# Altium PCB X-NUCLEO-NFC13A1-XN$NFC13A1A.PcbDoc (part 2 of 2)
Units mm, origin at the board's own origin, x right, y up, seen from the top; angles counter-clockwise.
Board outline 103.96 x 54 mm, 4 copper layers (Top Layer, F2-GND, F3, Bottom Layer), stack 1.17 mm thick; 113 components, 73 nets, 268 pads, 235 vias.

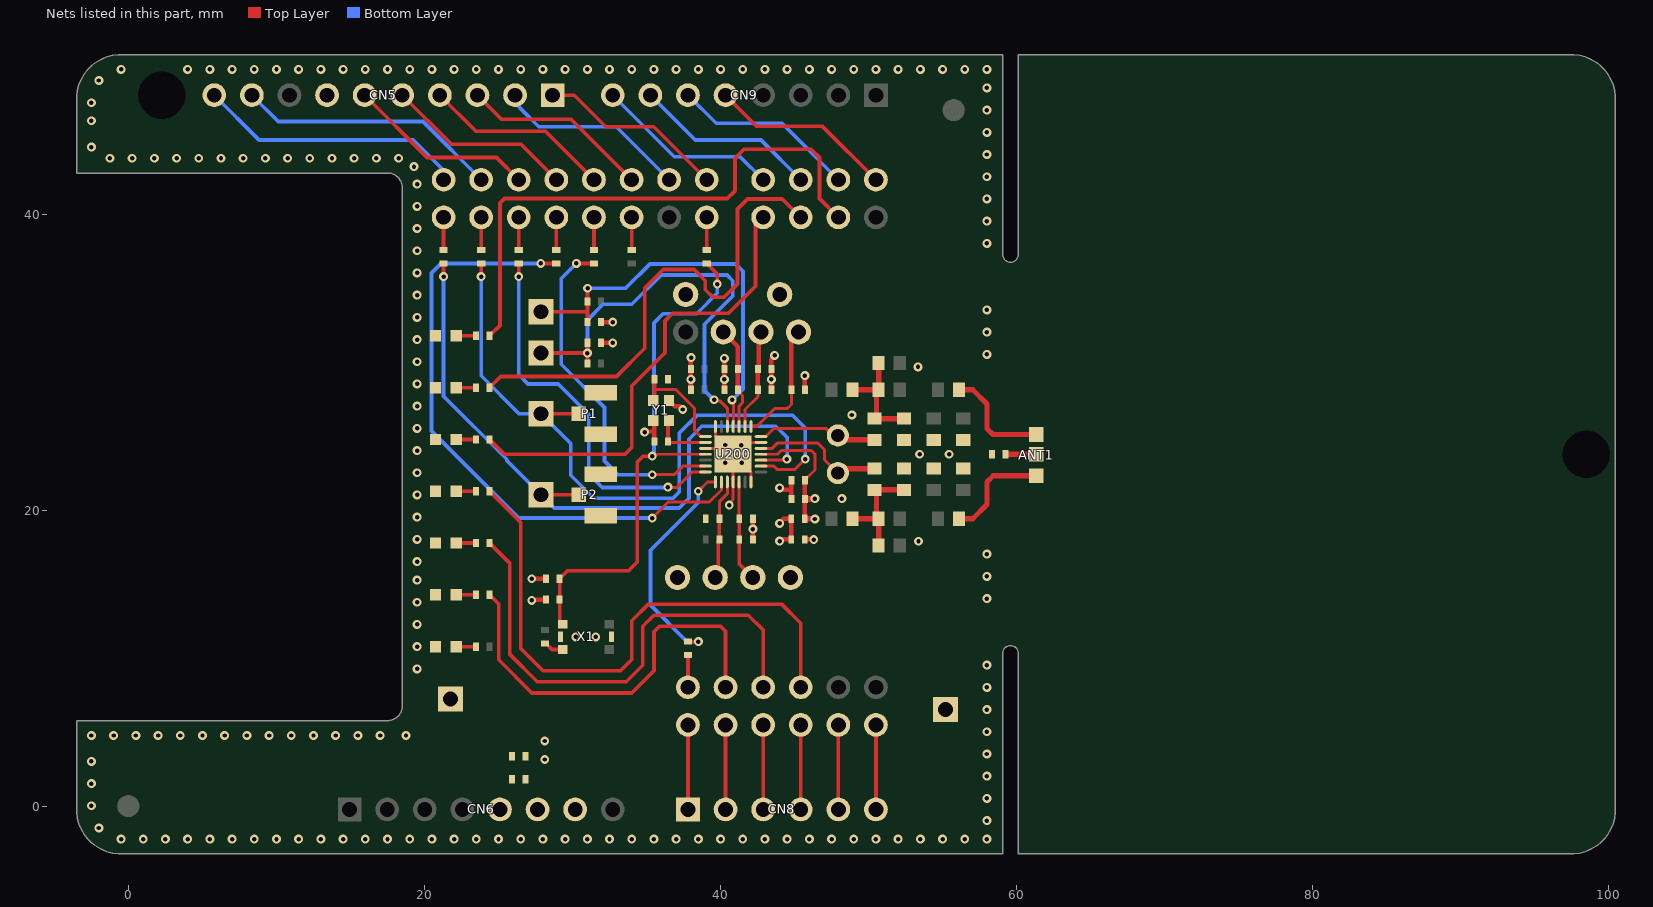
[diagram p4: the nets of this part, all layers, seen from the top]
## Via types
v1: diameter 0.6, hole 0.3, Top Layer to Bottom Layer, 225 vias
v2: diameter 1, hole 0.5, Top Layer to Bottom Layer, 10 vias

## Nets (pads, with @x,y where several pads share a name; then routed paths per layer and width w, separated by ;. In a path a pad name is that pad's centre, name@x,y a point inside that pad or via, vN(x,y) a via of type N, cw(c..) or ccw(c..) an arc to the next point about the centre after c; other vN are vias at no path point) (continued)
GND: C1.2 C2.2 C3.2 C4.2 C5.2 C6.2 C7.2 C8.2 C9.2 C10.2 C11.2 C12.2 C13.2 C14.2 C15.2 C16.2 C17.2 C22.1 C27.2 C28.2 C29.2 C30.1 C31.1 C32.1 C37.2 CN5.7 CN6.6 CN6.7 LED1.2 LED2.2 LED3.2 LED4.2 LED5.2 LED6.2 LED7.2 P1.2 P1.3 P2.2 P2.3 R17.1 R24.1 TP1.1 TP2.1 TP13.1 TP14.1 TP15.1 TP16.1 U200.4 U200.7 U200.13 U200.21 U200.24 U200.29 X1.5 X1.6 Y1.2 Y1.4 | length 28.1
  Top Layer w0.2: U200.24@38.993,24.17 40.118,24.17 U200.29@40.293,24.345 ; U200.21@39.668,25.645 39.668,24.97 40.243,24.395 v1(40.343,24.395) ; v1(40.601,20.329) 40.601,20.437 40.868,20.704 40.868,22.62 v1(41.443,23.195) 42.068,22.57 U200.7@42.068,21.895 U200.7@42.068,21.57 ; v1(41.418,24.37) 41.618,24.57 U200.13@42.743,24.57
  Top Layer w0.3: v1(27.252,13.897) 27.285,13.93 28.194,13.93 C2.2@28.227,13.963 ; v1(27.253,15.36) R17.1@28.227,15.36 ; C37.2@31.934,31.302 32.716,31.302 v1(32.73,31.288) ; C22.1@31.934,32.699 v1(32.73,32.699) ; v1(34.885,25.27) 34.922,25.307 35.542,25.307 ; Y1.4@35.474,26.053 35.542,25.985 35.542,25.307 ; C7.2@35.542,24.628 35.542,25.307 ; Y1.2@36.526,27.403 36.929,27 37.252,27 v1(37.458,26.793) ; C16.2@38.006,28.13 v1(38.006,28.828) C15.2@38.006,29.528 38.012,29.533 38.012,30.292 v1(38.018,30.297) ; C14.2@40.27,28.13 v1(40.27,28.829) C13.2@40.27,29.528 v1(40.27,30.249) ; C11.2@42.191,18.013 42.193,18.015 42.193,18.714 42.191,18.716 42.193,18.719 42.193,19.407 C12.2@42.191,19.41 ; C10.2@43.449,28.13 v1(43.449,28.829) C9.2@43.449,29.528 43.449,30.176 43.668,30.395 v1(43.668,30.45) v1@43.668,30.476 ; v1@43.992,21.381 44.798,21.381 ; C4.2@44.798,20.741 44.798,21.381 ; C5.2@44.798,22.022 44.798,21.381 ; C3.2@45.702,18.013 46.297,18.013 v1(46.31,18) ; C17.2@45.713,28.13 v1(45.713,29.079)
  other v1: -0.49,-2.23 1.01,-2.23 2.51,-2.23 4.01,-2.23 5.51,-2.23 7.01,-2.23 8.51,-2.23 10.01,-2.23 11.51,-2.23 13.01,-2.23 14.51,-2.23 16.01,-2.23 17.51,-2.23 19.01,-2.23 20.51,-2.23 22.01,-2.23 23.51,-2.23 25.01,-2.23 26.51,-2.23 28.01,-2.23 29.51,-2.23 31.01,-2.23 32.51,-2.23 34.01,-2.23 35.51,-2.23 37.01,-2.23 38.51,-2.23 40.01,-2.23 41.51,-2.23 43.01,-2.23 44.51,-2.23 46.01,-2.23 47.51,-2.23 49.01,-2.23 50.51,-2.23 52.01,-2.23 53.51,-2.23 55.01,-2.23 56.51,-2.23 58.01,-2.23 -1.99,-1.48 58.01,-0.98 -2.49,0.02 58.01,0.52 -2.49,1.52 58.01,2.02 -2.49,3.02 58.01,3.52 -2.49,4.77 -0.99,4.77 0.51,4.77 2.01,4.77 3.51,4.77 5.01,4.77 6.51,4.77 8.01,4.77 9.51,4.77 11.01,4.77 12.51,4.77 14.01,4.77 15.51,4.77 17.01,4.77 18.76,4.77 58.01,5.02 58.01,6.52 58.01,8.02 19.51,9.27 58.01,9.52 19.51,10.77 30.233,11.431 31.582,11.431 19.51,12.27 19.51,13.77 58.01,14.02 19.51,15.27 58.01,15.52 19.51,16.52 58.01,17.02 53.385,17.895 19.51,18.02 42.196,18.716 19.51,19.52 48.213,20.77 19.51,21.02 44,21.5 19.51,22.52 40.318,23.195 53.456,23.77 55.457,23.77 19.51,24.02 19.51,25.52 48.88,26.42 19.51,27.02 19.51,28.52 53.352,29.671 19.51,30.02 58.01,30.52 19.51,31.52 58.01,32.02 19.51,33.02 58.01,33.52 19.51,34.52 19.51,36.02 19.51,37.52 58.01,38.02 19.51,39.02 58.01,39.52 19.51,40.52 58.01,41.02 19.51,42.02 58.01,42.52 19.3,43.2 -1.24,43.77 0.26,43.77 1.76,43.77 3.26,43.77 4.76,43.77 6.26,43.77 7.76,43.77 9.26,43.77 10.76,43.77 12.26,43.77 13.76,43.77 15.26,43.77 16.76,43.77 18.26,43.77 58.01,44.02 -2.49,44.52 58.01,45.52 -2.49,46.3 58.01,47.02 -2.49,47.52 58.01,48.52 -1.99,49.02 -0.49,49.77 4.01,49.77 5.51,49.77 7.01,49.77 8.51,49.77 10.01,49.77 11.51,49.77 13.01,49.77 14.51,49.77 16.01,49.77 17.51,49.77 19.01,49.77 20.51,49.77 22.01,49.77 23.51,49.77 25.01,49.77 26.51,49.77 28.01,49.77 29.51,49.77 31.01,49.77 32.51,49.77 34.01,49.77 35.51,49.77 37.01,49.77 38.51,49.77 40.01,49.77 41.51,49.77 43.01,49.77 44.51,49.77 46.01,49.77 47.51,49.77 49.01,49.77 50.51,49.77 52.01,49.77 53.51,49.77 55.01,49.77 56.51,49.77 58.01,49.77
IO1: R15.2 ST1.1 | length 2.2
  Top Layer w0.25: R15.2@21.3,37.578 ST1.1@21.3,39.775
IO2: R14.2 ST2.1 | length 2.2
  Top Layer w0.25: R14.2@23.84,37.578 ST2.1@23.84,39.775
IRQ_210: R11.1 U200.1 | length 15.4
  Top Layer w0.2: v1(38.505,21.27) 39.13,21.895 U200.1@39.668,21.895
  Top Layer w0.25: R11.1@37.81,11.109 v1(38.51,11.109)
  Bottom Layer w0.25: v1(38.505,21.27) 38.505,20.508 35.276,17.278 35.276,13.585 37.751,11.109 v1(38.51,11.109)
LED1: R1.2 ST12.2 | length 28.2
  Top Layer w0.25: R1.2@24.407,14.27 25.019,13.659 25.019,9.886 27.26,7.645 34.01,7.645 35.51,9.145 35.51,11.77 35.885,12.145 40.01,12.145 40.35,11.805 ST12.2@40.35,8.025
LED2: R2.2 ST14.2 | length 33.6
  Top Layer w0.25: R2.2@24.407,17.77 25.76,16.417 25.76,10.27 27.635,8.395 33.635,8.395 34.76,9.52 34.76,12.145 35.51,12.895 41.885,12.895 42.89,11.89 ST14.2@42.89,8.025
LED3: R3.2 ST16.2 | length 39.3
  Top Layer w0.25: R3.2@24.407,21.27 26.51,19.167 26.51,10.645 28.01,9.145 33.26,9.145 34.01,9.895 34.01,12.52 35.135,13.645 44.135,13.645 45.43,12.35 ST16.2@45.43,8.025
LED4: R4.2 ST9.1 | length 31.6
  Top Layer w0.25: R4.2@24.407,24.77 25.407,23.77 33.551,23.77 34.01,24.229 34.01,28.385 36.26,30.635 36.26,32.77 36.786,33.296 40.546,33.296 42.375,35.125 42.375,39.26 ST9.1@42.89,39.775
LED5: R5.2 ST11.1 | length 34.1
  Top Layer w0.25: R5.2@24.407,28.27 25.157,29.02 32.978,29.02 34.885,30.926 34.885,34.999 36.136,36.25 38.227,36.25 38.985,35.492 38.985,34.89 39.5,34.375 40.25,34.375 41.15,35.275 41.15,40.341 41.829,41.02 44.185,41.02 ST11.1@45.43,39.775
LED6: R6.2 ST13.1 | length 38.4
  Top Layer w0.25: R6.2@24.407,31.77 25.11,32.473 25.11,40.745 25.41,41.045 40.467,41.045 40.985,41.563 40.985,43.762 41.598,44.375 46.143,44.375 46.7,43.818 46.7,41.045 ST13.1@47.97,39.775
MISO_210: R12.1 U200.2 | length 42.7
  Top Layer w0.2: v1(35.4,19.461) 36.469,20.53 39.236,20.53 40.068,21.362 U200.2@40.068,21.895
  Top Layer w0.25: v1(27.866,36.663) R12.1@28.92,36.663
  Bottom Layer w0.25: v1(27.866,36.663) 21.134,36.663 20.48,36.01 20.48,25.335 26.355,19.461 v1@35.368,19.461
MOSI_210: R9.1 U200.27 | length 23.6
  Top Layer w0.2: v1@35.51,22.386 36.89,22.386 37.47,22.966 U200.27@38.993,22.966
  Top Layer w0.25: v1(30.267,36.663) R9.1@31.46,36.663
  Bottom Layer w0.25: v1(30.267,36.663) 29.25,35.647 29.25,29.845 32.164,26.931 32.164,23.309 33.087,22.386 v1(35.4,22.386) v1@35.51,22.386
NetANT1_1: ANT1.1 R20.1 | length 7.5
  Top Layer w0.35: R20.1@56.118,28.13 57.05,28.13 58.01,27.169 58.01,25.494 58.409,25.095 ANT1.1@61.335,25.095
NetANT1_2: ANT1.2 R19.1 | length 7.3
  Top Layer w0.35: R19.1@56.118,19.41 57.05,19.41 58.01,20.37 58.01,21.895 58.435,22.32 ANT1.2@61.335,22.32
NetANT1_3: ANT1.3 R24.2 | length 2.1
  Top Layer w0.35: R24.2@59.257,23.77 ANT1.3@61.335,23.77
NetC23_1: C23.1 C25.2 C26.1 C27.1 L2.1 | length 7.7
  Top Layer w0.35: C25.2@48.929,19.41 C26.1@50.696,19.41 ; L2.1@50.406,21.37 L2.1@50.696,21.37 ; C23.1@50.696,17.59 C26.1@50.696,19.41 ; C27.1@52.407,21.37 L2.1@50.696,21.37 ; C26.1@50.696,19.41 50.551,19.554 50.551,21.225 L2.1@50.696,21.37
NetC30_2: C30.2 C33.1 C34.1 C35.1 L3.1 | length 7.4
  Top Layer w0.35: C34.1@48.929,28.13 C33.1@50.696,28.13 ; C35.1@50.696,29.93 C33.1@50.696,28.13 ; C30.2@52.407,26.17 50.696,26.17 50.551,26.314 50.551,27.985 C33.1@50.696,28.13
NetCN5_1: CN5.1 ST8.2 | length 12.8
  Top Layer w0.25: CN5.1@28.666,48.03 30.125,48.03 32.26,45.895 35.5,45.895 ST8.2@39.08,42.315
NetCN5_2: CN5.2 ST7.2 | length 13
  Bottom Layer w0.25: CN5.2@26.126,48.03 ccw(c27.408,48.03) 26.501,47.124 27.73,45.895 32.96,45.895 36.335,42.52 ST7.2@36.635,42.52
NetCN5_3: CN5.3 ST6.2 | length 12.8
  Top Layer w0.25: CN5.3@23.586,48.03 25.217,46.399 29.916,46.399 ST6.2@34,42.315
NetCN5_4: CN5.4 ST5.2 | length 12.8
  Top Layer w0.25: CN5.4@21.046,48.03 23.487,45.589 28.186,45.589 ST5.2@31.46,42.315
NetCN5_5: CN5.5 ST4.2 | length 12.8
  Top Layer w0.25: CN5.5@18.506,48.03 21.83,44.706 26.529,44.706 ST4.2@28.92,42.315
NetCN5_6: CN5.6 ST3.2 | length 12.8
  Top Layer w0.25: CN5.6@15.966,48.03 20.178,43.818 24.877,43.818 ST3.2@26.38,42.315
NetCN5_9: CN5.9 ST2.2 | length 17.9
  Bottom Layer w0.25: CN5.9@8.346,48.03 10.126,46.25 19.905,46.25 ST2.2@23.84,42.315
NetCN5_10: CN5.10 ST1.2 | length 18.2
  Bottom Layer w0.25: CN5.10@5.806,48.03 8.836,45 19.25,45 21.3,42.95 ST1.2@21.3,42.315
NetCN8_1: CN8.1 ST10.1 | length 5.7
  Top Layer w0.25: CN8.1@37.81,-0.23 ST10.1@37.81,5.485
NetCN8_2: CN8.2 ST12.1 | length 5.7
  Top Layer w0.25: CN8.2@40.35,-0.23 ST12.1@40.35,5.485
NetCN8_3: CN8.3 ST14.1 | length 5.7
  Top Layer w0.25: CN8.3@42.89,-0.23 ST14.1@42.89,5.485
NetCN8_4: CN8.4 ST16.1 | length 5.7
  Top Layer w0.25: CN8.4@45.43,-0.23 ST16.1@45.43,5.485
NetCN8_5: CN8.5 ST18.1 | length 5.7
  Top Layer w0.25: CN8.5@47.97,-0.23 ST18.1@47.97,5.485
NetCN8_6: CN8.6 ST20.1 | length 5.7
  Top Layer w0.25: CN8.6@50.51,-0.23 ST20.1@50.51,5.485
NetCN9_5: CN9.5 ST15.2 | length 12.5
  Top Layer w0.25: CN9.5@40.35,48.03 42.46,45.92 46.905,45.92 ST15.2@50.51,42.315
NetCN9_6: CN9.6 ST13.2 | length 12.8
  Top Layer w0.25: ST13.2@47.939,42.579 47.939,42.346 ST13.2@47.97,42.315
  Bottom Layer w0.25: CN9.6@37.81,48.03 39.715,46.125 44.16,46.125 ST13.2@47.97,42.315
NetCN9_7: CN9.7 ST11.2 | length 12.5
  Bottom Layer w0.25: CN9.7@35.27,48.03 38.3,45 42.745,45 ST11.2@45.43,42.315
NetCN9_8: CN9.8 ST9.2 | length 12.5
  Bottom Layer w0.25: CN9.8@32.73,48.03 36.885,43.875 41.33,43.875 ST9.2@42.89,42.315
NetLED1_1: LED1.1 R1.1 | length 1.3
  Top Layer w0.25: LED1.1@22.149,14.27 R1.1@23.493,14.27
NetLED2_1: LED2.1 R2.1 | length 1.3
  Top Layer w0.25: LED2.1@22.149,17.77 R2.1@23.493,17.77
NetLED3_1: LED3.1 R3.1 | length 1.3
  Top Layer w0.25: LED3.1@22.149,21.27 R3.1@23.493,21.27
NetLED4_1: LED4.1 R4.1 | length 1.3
  Top Layer w0.25: LED4.1@22.149,24.77 R4.1@23.493,24.77
NetLED5_1: LED5.1 R5.1 | length 1.3
  Top Layer w0.25: LED5.1@22.149,28.27 R5.1@23.493,28.27
NetLED6_1: LED6.1 R6.1 | length 1.3
  Top Layer w0.25: LED6.1@22.149,31.77 R6.1@23.493,31.77
NetLED7_1: LED7.1 R7.1 | length 1.3
  Top Layer w0.25: LED7.1@22.149,10.77 R7.1@23.493,10.77
NetR16_1: R16.1 X1.2 | length 1.4
  Top Layer w0.25: R16.1@28.149,10.974 28.228,10.974 28.621,10.581 X1.2@29.349,10.581
RESET: R13.2 ST8.1 | length 2.2
  Top Layer w0.25: R13.2@39.08,37.578 ST8.1@39.08,39.775
RESET_210: C2.1 R13.1 R17.2 U200.25 X1.4 | length 36.9
  Top Layer w0.2: v1(35.4,23.645) 35.477,23.721 35.668,23.721 35.717,23.77 U200.25@38.993,23.77
  Top Layer w0.25: X1.4@29.349,12.281 29.142,12.489 C2.1@29.142,13.963 R17.2@29.142,15.36 29.677,15.895 33.798,15.895 34.385,16.482 34.385,23.24 34.79,23.645 v1(35.4,23.645) ; R13.1@39.08,36.663 39.788,35.956 v1(39.788,35.264)
  Bottom Layer w0.25: v1@35.51,23.645 35.51,32.645 36.13,33.265 38.396,33.265 39.788,34.658 v1(39.788,35.264)
RFI1: C22.2 C24.1 TP4.1 U200.18 | length 27.6
  Top Layer w0.2: U200.18@40.872,25.645 40.872,27.123 40.867,27.128 40.867,27.495 v1@40.872,27.5
  Top Layer w0.25: TP4.1@27.883,33.397 27.885,33.398 31.02,33.398 ; C22.2@31.02,32.699 31.02,33.398 ; v1(31.029,34.982) 31.02,34.972 C24.1@31.02,34.096 31.02,33.398
  Bottom Layer w0.25: v1(31.029,34.982) 33.597,34.982 35.24,36.625 41.03,36.625 41.53,36.125 41.53,28.155 v1@40.875,27.5
  other v1: 40.79,27.44
RFI2: C36.2 C37.1 TP5.1 U200.19 | length 29.4
  Top Layer w0.2: v1(39.58,27.45) 39.648,27.382 39.96,27.382 40.468,26.874 U200.19@40.468,25.645
  Top Layer w0.25: TP5.1@27.884,30.604 v1(31.02,30.604) ; C36.2@31.02,29.905 v1(31.02,30.604) ; C37.1@31.02,31.302 v1(31.02,30.604)
  Bottom Layer w0.25: v1(31.02,30.604) 31.02,32.846 32.077,33.903 34.018,33.903 35.99,35.875 40.444,35.875 40.831,35.488 40.831,34.456 38.925,32.55 38.925,28.075 v1@39.5,27.5
RFO1: J1.1 L2.2 U200.12 | length 9.2
  Top Layer w0.2: U200.12@42.743,24.17 43.497,24.17 43.847,24.52 46.588,24.52 47.038,24.07 47.038,23.401 47.514,22.925 47.897,22.925 J1.1@47.939,22.966
  Top Layer w0.25: J1.1@47.939,22.5 J1.1@47.939,22.966
  Top Layer w0.35: J1.1@48.172,22.5 48.464,22.793 L2.2@50.406,22.793
RFO2: J1.2 L3.2 U200.14 | length 8.2
  Top Layer w0.2: U200.14@42.743,24.97 43.068,24.97 43.618,25.52 47.121,25.52 J1.2@47.601,25.04
  Top Layer w0.25: J1.2@47.601,25.04 J1.2@47.647,25.04
  Top Layer w0.35: J1.2@47.647,25.04 J1.2@47.939,25.04 48.232,24.747 L3.2@50.406,24.747
SCLK_210: R10.1 U200.28 | length 26.1
  Top Layer w0.2: v1@36.486,21.52 37.051,21.52 38.101,22.57 U200.28@38.993,22.57
  Top Layer w0.25: v1(26.38,35.77) R10.1@26.38,36.663 ; v1(36.457,21.549) v1@36.486,21.52
  Bottom Layer w0.25: v1(26.38,35.77) 26.38,29.14 27,28.52 29.04,28.52 31.116,26.445 31.116,22.421 32.017,21.52 36.427,21.52 v1(36.457,21.549)
SPI_BSS: R8.2 ST6.1 | length 2.2
  Top Layer w0.25: R8.2@34.011,37.578 ST6.1@34.011,39.775
SPI_IRQ: R11.2 ST10.2 | length 2.2
  Top Layer w0.25: ST10.2@37.81,8.025 R11.2@37.81,10.195
SPI_MISO: R12.2 ST4.1 | length 2.2
  Top Layer w0.25: R12.2@28.92,37.578 ST4.1@28.92,39.775
SPI_MOSI: R9.2 ST5.1 | length 2.2
  Top Layer w0.25: R9.2@31.46,37.578 ST5.1@31.46,39.775
SPI_SCLK: R10.2 ST3.1 | length 2.2
  Top Layer w0.25: R10.2@26.38,37.578 ST3.1@26.38,39.775
TAD1_210: P1.1 R14.1 TP3.1 U200.9 | length 47.2
  Top Layer w0.2: U200.9@42.743,22.97 43.601,22.97 43.821,22.75 45.04,22.75 v1(45.735,23.445)
  Top Layer w0.25: v1(23.84,35.77) R14.1@23.84,36.663 ; TP3.1@27.883,26.51 P1.1@30.427,26.51
  Bottom Layer w0.25: v1(23.84,35.77) 23.84,29.066 26.396,26.51 TP3.1@27.883,26.51 29.894,24.499 29.894,22.358 31.451,20.801 36.797,20.801 37.221,21.225 37.221,25.201 38.415,26.395 44.885,26.395 45.735,25.545 v1(45.735,23.445)
TAD2_210: P2.1 R15.1 TP6.1 U200.10 | length 46.3
  Top Layer w0.2: U200.10@42.743,23.37 44.42,23.37 v1(44.495,23.445)
  Top Layer w0.25: v1(21.3,35.77) R15.1@21.3,36.663 ; TP6.1@27.883,21.03 P2.1@30.427,21.03 ; v1@44.4,23.445 v1(44.495,23.445)
  Bottom Layer w0.25: v1(21.3,35.77) 21.3,27.686 25.56,23.425 25.56,23.353 TP6.1@27.883,21.03 28.773,20.141 37.221,20.141 37.875,20.795 37.875,24.787 38.747,25.66 43.745,25.66 44.51,24.895 44.51,23.46 v1(44.495,23.445) v1@44.42,23.52
V_RF: C3.1 L1.2 R23.1 | length 3
  Top Layer w0.3: v1@44,19.15 44.26,19.41 L1.2@44.788,19.41 C3.1@44.788,18.013 v1@44.08,18.013
  other v1: 28.135,3.145 28.135,4.395 44,17.9 44,19.1
VBUS: C1.1 CN6.5 R23.2
VDD: C4.1 C5.1 C9.1 C10.1 L1.1 TP12.1 U200.11 U200.16 | length 16.3
  Top Layer w0.2: U200.16@41.668,25.645 41.668,26.793 42.535,27.66 C10.1@42.535,28.13 ; U200.11@42.743,23.77 43.865,23.77 44.114,24.02 46.135,24.02 46.385,23.77 46.385,22.714 C5.1@45.847,22.176
  Top Layer w0.3: C10.1@42.535,28.13 C9.1@42.535,29.528 42.585,29.578 42.585,31.877 TP12.1@42.535,31.927 ; L1.1@45.702,19.41 L1.1@45.713,19.41 ; L1.1@45.707,19.415 45.707,20.735 C4.1@45.713,20.741 C5.1@45.713,22.022
  Top Layer w0.4: L1.1@45.713,19.41 46.37,19.41 v1(46.385,19.395) ; C4.1@45.713,20.741 46.356,20.741 v1(46.385,20.77)
VDD_A: C13.1 C14.1 TP11.1 U200.17 | length 6.8
  Top Layer w0.2: C14.1@41.185,28.051 41.5,27.736 41.5,27.25 41.268,27.018 U200.17@41.268,25.645
  Top Layer w0.25: C14.1@41.185,28.051 C14.1@41.185,28.13
  Top Layer w0.3: TP11.1@40.446,31.927 40.446,31.777 41.185,31.038 C13.1@41.185,29.528 C14.1@41.185,28.13
VDD_D: C11.1 C12.1 TP10.1 U200.5 | length 6.8
  Top Layer w0.2: C12.1@41.268,19.418 U200.5@41.268,21.895
  Top Layer w0.25: C12.1@41.276,19.41 C11.1@41.276,18.013 41.276,16.361 TP10.1@42.189,15.448
VDD_DR: C17.1 TP8.1 U200.15 | length 8
  Top Layer w0.2: U200.15@42.068,25.645 42.464,25.645 43.674,26.855 44.516,26.855 44.798,27.137 C17.1@44.798,28.13
  Top Layer w0.3: C17.1@44.798,28.13 TP8.1@44.798,31.752
VDD_IO: C8.1 R18.1 TP7.1 U200.3 | length 6.1
  Top Layer w0.2: C8.1@39.927,19.41 39.927,20.555 40.468,21.096 U200.3@40.468,21.895
  Top Layer w0.25: TP7.1@39.927,16.104 39.852,16.179 39.852,17.938 R18.1@39.927,18.013 C8.1@39.927,19.41
XTI: C6.1 U200.22 Y1.3 | length 7
  Top Layer w0.2: 35.542,28.153 36.972,28.153 38.25,26.875 38.25,25.388 38.668,24.97 U200.22@38.993,24.97
  Top Layer w0.25: Y1.3@35.542,27.471 35.542,28.153 C6.1@35.542,28.829
XTO: C7.1 U200.23 Y1.1 | length 4
  Top Layer w0.2: C7.1@36.457,24.628 36.515,24.57 U200.23@38.993,24.57
  Top Layer w0.25: C7.1@36.457,24.628 Y1.1@36.457,25.983 ; Y1.1@36.657,25.983 Y1.1@36.726,26.053
pads on no net: CN5.8 CN6.1 CN6.2 CN6.3 CN6.8 CN9.1 CN9.2 CN9.3 CN9.4 MIR1.1 MIR2.1 ST7.1 ST15.1 ST18.2 ST20.2 X1.1 X1.3
copper on no net: | length 40
  Top Layer w0.2: 1.76,2.47 1.76,3.72 ; 1.76,2.47 0.51,2.47 0.51,3.72 1.76,3.72 ; 1.76,2.47 1.76,3.72 ; 1.76,2.47 3.01,2.47 ; 1.76,3.72 3.01,3.72 ; 3.01,2.47 3.01,3.72 ; 3.01,2.47 3.01,3.72 ; 3.01,2.47 4.26,2.47 ; 3.01,3.72 4.26,3.72 ; 4.26,2.47 4.26,3.72 ; 4.26,2.47 4.26,3.72 ; 4.26,2.47 5.51,2.47 5.51,3.72 4.26,3.72
  Bottom Layer w0.2: 1.76,2.47 3.01,2.47 ; 1.76,2.47 1.76,3.72 ; 1.76,2.47 0.51,2.47 0.51,3.72 1.76,3.72 ; 1.76,2.47 1.76,3.72 ; 1.76,3.72 3.01,3.72 ; 3.01,2.47 4.26,2.47 ; 3.01,2.47 3.01,3.72 ; 3.01,2.47 3.01,3.72 ; 3.01,3.72 4.26,3.72 ; 4.26,2.47 5.51,2.47 5.51,3.72 4.26,3.72 ; 4.26,2.47 4.26,3.72 ; 4.26,2.47 4.26,3.72
  other v2: 63.226,22.32 65.714,22.324 92.473,22.325 94.994,22.329 63.235,23.77 66.976,23.77 63.226,25.095 64.473,25.215 93.714,25.215 96.235,25.22

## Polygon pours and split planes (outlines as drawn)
GND on Top Layer "NONET_L03_P-001" (solid, remove dead copper, pour order 471): -3.49,50.77 58.5,50.77 58.5,-3.23 -3.49,-3.23
V_RF on Top Layer "NONET_L03_P-001" (solid, remove dead copper, pour order 468): 26.625,2.75 26.625,4.77 28.5,4.77 28.5,2.75
VBUS on Top Layer "NONET_L03_P-001" (solid, pour order 470): 26.115,-1.5 26.115,4.75 24.125,4.75 24.125,-1.5
no net on Top Solder "NONET_L03_P-001" (solid, pour order 474): 0.26,3.895 5.76,3.895 5.76,2.27 0.26,2.27
no net on Bottom Solder "NONET_L03_P-001" (solid, pour order 475): 0.26,3.895 5.76,3.895 5.76,2.27 0.26,2.27
VDD on F3 "NONET_L03_P-001" (solid, pour order 479): 48,12 36.125,12 36.125,2.25 24.375,2.25 24.375,-3.25 58.5,-3.25 58.5,50.875 -3.5,50.875 -3.5,20 45.5,20 45.5,18 48,18
3V3 on F3 "NONET_L03_P-001" (solid, pour order 477): -4.625,-3.23 23.875,-3.23 23.875,9.375 28.75,9.375 28.75,17.5 38.75,17.5 38.75,19.5 -4.625,19.5
V_RF on F3 "NONET_L03_P-001" (solid, pour order 478): 47.5,12.5 35.625,12.5 35.625,2.75 24.375,2.75 24.375,8.875 29.25,8.875 29.25,17 39.25,17 39.25,19.5 45,19.5 45,17.5 47.5,17.5
GND on F2-GND "NONET_L03_P-001" (solid, pour order 472): -3.49,50.77 58.5,50.77 58.5,-3.23 -3.49,-3.23
GND on Bottom Layer "BTM_GND" (solid, remove dead copper, pour order 473): 58.5,58.731 58.5,-11.272 -4.44,-11.272 -4.44,58.731

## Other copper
Top Layer:
  pour cut-out: 42.494,20.568 42.994,20.568 42.994,22.212 42.494,22.212
  pour cut-out: 48.113,28.188 48.822,28.188 48.822,29.807 48.113,29.807
  pour cut-out: 44.598,25.75 45.098,25.75 45.098,27 44.598,27
  pour cut-out: 42.793,26.544 43.293,26.544 43.293,27.794 42.793,27.794
  pour cut-out: 37.234,24.891 37.734,24.891 37.734,26.141 37.234,26.141
  pour cut-out: 49.724,25 53.875,25 53.875,26.375 49.724,26.375
  pour cut-out: 48.072,18.842 48.572,18.842 48.572,20.092 48.072,20.092
  pour cut-out: 48.113,27.755 48.113,27.448 48.322,27.448 48.322,27.83 48.188,27.83
  pour cut-out: 33.375,30.063 34.125,30.063 34.125,31.437 33.375,31.438
  pour cut-out: 35.954,29.062 36.25,29.062 36.25,30.218 35.954,30.218
  pour cut-out: 40.75,32.375 42,32.375 42,34.5 40.75,34.5
  pour cut-out: 54.875,25 55.875,25 55.875,26.375 54.875,26.375
  pour cut-out: 55.102,25.154 58.75,25.154 58.75,28.812 55.102,28.812
  pour cut-out: 55.102,18.75 58.5,18.75 58.5,22.386 55.102,22.386
  pour cut-out: 49.724,21 57,21 57,22.625 49.724,22.625
  pour cut-out: 50.5,23.125 51.089,23.125 51.089,24.375 50.5,24.375
  pour cut-out: 45,18.375 45.5,18.375 45.5,19.625 45,19.625
  pour cut-out: 46.375,19.375 46.875,19.375 46.875,21.5 46.375,21.5
  pour cut-out: 45.938,21.5 47.562,21.5 47.562,22.75 45.938,22.75
  pour cut-out: 37.125,43.375 41.75,43.375 41.75,44.625 37.125,44.625
  pour cut-out: 15.75,47.75 29.375,47.75 29.375,49 15.75,49
  pour cut-out: 22.875,35.25 25.125,35.25 25.125,42.315 22.875,42.315
  pour cut-out: 20.3,42.315 25.75,42.315 25.75,43.512 20.3,43.512
  pour cut-out: 31.25,29.875 31.75,29.875 31.75,31.125 31.25,31.125
  pour cut-out: 31.25,32.625 31.75,32.625 31.75,33.875 31.25,33.875
  pour cut-out: 31.875,37 33.625,37 33.625,38.25 31.875,38.25
  pour cut-out: 26.875,36.125 30.25,36.125 30.25,37.625 26.875,37.625
  pour cut-out: 31.375,34.25 31.875,34.25 31.875,35.5 31.375,35.5
  pour cut-out: 25.375,35.25 26.375,35.25 26.375,36.5 25.375,36.5
  pour cut-out: 43.25,38.75 48,38.75 48,43.25 43.25,43.25
  pour cut-out: 38.25,28.125 38.75,28.125 38.75,29.375 38.25,29.375
  pour cut-out: 36.375,30.625 40.875,30.625 40.875,31.875 36.375,31.875
  pour cut-out: 40.5,28.25 41,28.25 41,29.5 40.5,29.5
  pour cut-out: 34.375,26.25 34.875,26.25 34.875,27.75 34.375,27.75
  pour cut-out: 35.75,24.375 36.25,24.375 36.25,25.625 35.75,25.625
  pour cut-out: 39.25,18.25 39.75,18.25 39.75,20.25 39.25,20.25
  pour cut-out: 28.375,12.25 28.875,12.25 28.875,13.5 28.375,13.5
  pour cut-out: 28.125,9.5 29.875,9.5 29.875,11 28.125,11
  pour cut-out: 21,11.25 26.25,11.25 26.25,18.661 24.161,20.75 21,20.75
  pour cut-out: 34,7.375 34.375,7 46.375,7 46.375,11.75 44.25,13.875 35,13.875 34,12.875 34,8.625
  pour cut-out: 28.382,15.176 29.017,15.176 29.017,14.16 28.382,14.16
  text "- TOP LAYER -" at 34.629,56 h1.5
  text "1" at 1.01,2.72 h0.75
F2-GND:
  pour cut-out: 0.26,3.895 5.76,3.895 5.76,2.27 0.26,2.27
  text "- INT1 -" at 40,56 h1.5
  text "2" at 2.135,2.72 h0.75
F3:
  pour cut-out: 39.919,24.678 41.842,24.678 41.842,22.937 41.867,22.912 39.894,22.912
  pour cut-out: 0.26,3.895 5.76,3.895 5.76,2.27 0.26,2.27
  text "- INT2 -" at 40,56 h1.5
  text "3" at 3.385,2.72 h0.75
Bottom Layer:
  pour cut-out: 44.353,22.87 44.875,22.87 44.875,17.625 44.412,17.625
  pour cut-out: 48.369,29.909 49.114,29.909 49.114,28.375 48.386,28.375
  pour cut-out: 44.847,26.673 46.644,26.673 46.644,25.875 44.856,25.875
  pour cut-out: 40.629,37.125 41.882,37.125 41.882,36.327 40.638,36.327
  pour cut-out: 35.747,33.048 41.53,33.048 41.53,30.875 35.771,30.875
  pour cut-out: 34.122,24.798 37.125,24.798 37.125,24 34.131,24
  pour cut-out: 31.362,30.625 33.75,30.625 33.75,29.25 31.378,29.25
  pour cut-out: 27.866,37.173 31.5,37.173 31.5,36.375 27.875,36.375
  text "- BOT LAYER -" at 58.6,56.2 h1.5
  text "4" at 5.21,2.72 h0.75

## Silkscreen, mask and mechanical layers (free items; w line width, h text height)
Top Overlay:
  drawing of 444 lines, arcs and shapes, not listed
  text "- TOP OVERLAY -" at 36.375,56 h1.5
  text "GND" at 38.005,35.926 h0.7 r90
  text "GND" at 44.355,35.93 h0.7 r90
  text "VDD_A" at 40.599,33.162 h0.7 r90
  text "VDD" at 42.335,33.162 h0.7 r90
  text "VDD_DR" at 45.913,33.162 h0.7 r90
  text "RFI1" at 23.617,32.915 h0.7
  text "LED6" at 20.227,32.75 h0.7
  text "AGD" at 36.42,32.332 h0.7 r90
  text "RFI2" at 23.617,30.254 h0.7
  text "LED5" at 20.227,29.25 h0.7
  text "TAD2" at 23.617,26.17 h0.7
  text "LED4" at 20.227,25.75 h0.7
  text "RFO2" at 44.86,23.487 h0.7 r90
  text "RFO1" at 46.085,22.832 h0.7 r90
  text "LED3" at 20.227,22.25 h0.7
  text "ST25" at 81.602,22.213 h1.56 r90
  text "TAD1" at 23.617,19.446 h0.7
  text "LED2" at 20.227,18.75 h0.7
  text "LED1" at 20.344,15.25 h0.7
  text "GND" at 37.458,12.203 h0.7 r90
  text "GND" at 44.005,12.203 h0.7 r90
  text "PWR OK" at 20.017,11.82 h0.7
  text "VDD_D" at 42.481,10.804 h0.7 r90
  text "VDD_IO" at 39.998,10.221 h0.7 r90
  text "www.st.com/nucleo-nfc" at 70,8.72 h3.4 r90
  text "RESET" at 29.874,8.595 h0.7
  text "GND" at 20.128,6.292 h0.7 r90
  text "X-NUCLEO-NFC13A1" at 90.02,6.25 h4 r90
  text "GND" at 53.48,5.587 h0.7 r90
  text "V_RF" at 26.312,5.442 h0.7
  text "XN$NFC13A1A" at 9.693,2.925 h1.4
  text "Nucleo" at 10.85,-1.732 h0.7 r90
Bottom Overlay:
  drawing of 245 lines, arcs and shapes, not listed
  text "- BOTTOM OVERLAY -" at 9.625,55.25 h1.5
  text "FCCID:YCPNFC13A1" at 85.476,41.455 h5 r89.84
  text "IC:8976A-NFC13A1" at 89.55,39.76 h5 r89.95
  text "X-NUCLEO-NFC13A1" at 80.028,38.795 h4.15 r90.06
Top Paste:
  lines w0.2: 59.6,35.484 59.499,35.484 59.312,35.407 59.169,35.264 59.092,35.077 59.092,34.976 59.092,26.562 59.169,26.375 59.312,26.232 59.499,26.155 59.701,26.155 59.888,26.232 60.031,26.375 60.108,26.562 60.108,35.077 60.031,35.264 59.888,35.407 59.701,35.484 59.6,35.484 ; 59.6,35.484 59.6,35.484 ; 60.108,37.254 60.108,37.153 60.031,36.966 59.888,36.823 59.701,36.746 59.6,36.746 59.499,36.746 59.312,36.823 59.169,36.966 59.092,37.153 59.092,37.254 59.092,50.77 -0.687,50.77 -1.077,50.719 -1.458,50.617 -1.821,50.466 -2.162,50.269 -2.475,50.029 -2.753,49.751 -2.993,49.439 -3.19,49.098 -3.341,48.734 -3.443,48.353 -3.494,47.963 -3.494,47.766 -3.49,42.77 17.51,42.77 cw(c17.51,41.77) 18.51,41.77 18.51,6.77 cw(c17.51,6.77) 17.51,5.77 -3.49,5.77 -3.49,-0.427 -3.439,-0.817 -3.337,-1.196 -3.186,-1.56 -2.99,-1.9 -2.75,-2.212 -2.472,-2.49 -2.16,-2.73 -1.82,-2.926 -1.456,-3.077 -1.077,-3.179 -0.687,-3.23 59.092,-3.23 59.092,10.439 59.169,10.626 59.312,10.769 59.499,10.846 59.701,10.846 59.888,10.769 60.031,10.626 60.108,10.439 60.108,-3.23 97.664,-3.23 98.054,-3.179 98.434,-3.077 98.797,-2.926 99.138,-2.73 99.45,-2.49 99.728,-2.212 99.967,-1.9 100.164,-1.56 100.314,-1.196 100.416,-0.817 100.467,-0.427 100.467,47.967 100.416,48.357 100.314,48.736 100.164,49.1 99.967,49.44 99.728,49.752 99.45,50.03 99.138,50.27 98.797,50.466 98.434,50.617 98.054,50.719 97.664,50.77 60.108,50.77 60.108,37.254 ; 60.108,37.254 60.108,37.254 ; 59.092,12.515 59.169,12.328 59.312,12.185 59.499,12.108 59.701,12.108 59.888,12.185 60.031,12.328 60.108,12.515 60.108,20.903 60.031,21.09 59.888,21.233 59.701,21.31 59.499,21.31 59.312,21.233 59.169,21.09 59.092,20.903 59.092,12.515
  text "- TOP PASTE MASK -" at 38.179,56 h1.5
Bottom Paste:
  text "- BOTTOM PASTE MASK -" at 9.625,55.125 h1.5
Top Solder:
  lines w0.5: 17.458,42.77 -3.49,42.77 -3.494,47.766 cw(c-0.588,47.865) -0.687,50.77 59.092,50.77 59.092,37.254 ccw(c59.6,37.254) 60.108,37.254 ; 17.509,42.77 cw(c17.509,41.77) 18.509,41.77 ; 17.51,5.77 ccw(c17.51,6.77) 18.51,6.77 ; 17.558,5.77 -3.49,5.77 -3.49,-0.427 ccw(c-0.687,-0.427) -0.687,-3.23 59.092,-3.23 59.092,10.338 cw(c59.6,10.338) 60.108,10.338 60.108,-3.23 97.664,-3.23 ccw(c97.664,-0.427) 100.467,-0.427 100.467,47.967 ccw(c97.664,47.967) 97.664,50.77 60.108,50.77 60.108,37.254 ; 18.51,6.722 18.51,41.718 ; 60.108,37.254 60.108,37.254 ; 59.092,12.616 ccw(c59.6,12.616) 60.108,12.616 60.108,20.801 ccw(c59.6,20.801) 59.092,20.801 59.092,12.616 ; 59.092,26.663 ccw(c59.6,26.663) 60.108,26.663 60.108,34.976 ccw(c59.6,34.976) 59.092,34.976 59.092,26.663
  text "- TOP SOLDER MASK -" at 36.375,56 h1.5
Bottom Solder:
  lines w0.5: 17.509,42.77 cw(c17.509,41.77) 18.509,41.77 ; 17.51,5.77 ccw(c17.51,6.77) 18.51,6.77 ; 17.51,42.77 -3.49,42.77 -3.494,47.766 cw(c-0.588,47.865) -0.687,50.77 59.092,50.77 59.092,37.254 ccw(c59.6,37.254) 60.108,37.254 60.108,50.77 97.664,50.77 cw(c97.664,47.967) 100.467,47.967 100.467,-0.427 cw(c97.664,-0.427) 97.664,-3.23 60.108,-3.23 60.108,10.338 ccw(c59.6,10.338) 59.092,10.338 59.092,-3.23 -0.687,-3.23 cw(c-0.687,-0.427) -3.49,-0.427 -3.49,5.77 17.558,5.77 ; 18.51,6.722 18.51,41.77 ; 59.092,12.616 ccw(c59.6,12.616) 60.108,12.616 60.108,20.802 ccw(c59.6,20.802) 59.092,20.802 59.092,12.616 ; 59.092,26.663 ccw(c59.6,26.663) 60.108,26.663 60.108,34.976 ccw(c59.6,34.976) 59.092,34.976 59.092,26.663
  text "- BOTTOM SOLDER MASK -" at 9.625,55.125 h1.5
Top Assembly:
  region: 155.51,27.77 154.51,25.77 153.51,27.77
  lines w0.2: 154.51,18.77 154.51,27.77 ; 145.833,29.27 147.031,28.27 146.531,27.77 163.281,27.77 162.531,28.77 163.031,29.27 145.833,29.27 ; 152.51,29.27 152.51,38.27 156.51,38.27 156.51,29.27 152.51,29.27
  text ".Board_Reference" at -26.175,55.05 h1.5
  text "CN5/CN6/CN8/CN9 ASSEMBLY DETAIL" at 126.51,40.77 h2
  text "TOP LAYER" at 158.51,33.77 h1.2
  text "DO NOT CUT" at 155.51,22.77 h1.2
  text "U200" at 35.149,21.173 h0.7
  text "KEEP THE WHOLE PINS LENGTH" at 155.51,20.77 h1.2
  text "X1" at 30.504,8.879 h0.6
  text "RoHS COMPLIANT PRODUCT" at 25.488,-10.078 h1.5
  text "TOP ASSEMBLY DRAWING" at 103,-109.001 h2
  text "01/01" at 240.91,-134.28 h2.1
Bottom Assembly:
  text "BOTTOM ASSEMBLY DRAWING" at 10,-108.78 h2
  text "02/02" at -122.59,-134.28 h2
Drill Drawing:
  drawing of 186 lines, arcs and shapes, not listed
  text "BOARD DESIGN CONCEPTION VALUES" at 167.19,108.39 h1.75
  text "SPECIFIED VALUES ARE MINIMUM. USED VALUES MAY BE LARGER" at 157.19,105.39 h1.4
  text "EXTERNAL" at 191.425,100.63 h1.4
  text "INTERNAL" at 212.38,100.63 h1.4
  text "LAYERS" at 191.425,98.09 h1.4
  text "LAYERS" at 212.38,98.09 h1.4
  text "FINISHED HOLE" at 190.41,94.22 h1.4
  text "FINISHED HOLE" at 212.66,94.22 h1.4
  text "PLATED HOLES" at 157.135,93.645 h1.4
  text "MIN. ANNULAR RING" at 157.135,91.105 h1.4
  text "0.30mm" at 196.505,91.105 h1.4
  text "0.30mm" at 218.755,91.105 h1.4
  text "+" at 193.33,90.47 h2.1
  text "+" at 215.58,90.47 h2.1
  text "DRILL HOLE" at 192.16,87.39 h1.4
  text "DRILL HOLE" at 214.41,87.39 h1.4
  text "VIA MINIMUM" at 156.5,86.66 h1.4
  text "0.15mm" at 196.66,84.39 h1.4
  text "0.15mm" at 218.91,84.39 h1.4
  text "ANNULAR RING" at 156.5,84.12 h1.4
  text "+" at 193.66,83.89 h2.1
  text "+" at 215.91,83.89 h2.1
  text "HOLE TO HOLE" at 156.5,79.675 h1.4
  text "0.35mm" at 193.91,78.72 h1.4
  text "MINIMUM CLEARANCE" at 156.5,77.135 h1.4
  text "TOP LAYER VIEW" at 23.25,70.5 h3
  text "MINIMUM TRACK WIDTH" at 156.555,68.005 h1.4
  text "0.25" at 211.8,68.005 h1.4
  text "MINIMUM CLEARANCE" at 155.92,63.56 h1.4
  text "0.2mm" at 211.8,62.29 h1.4
  text "BETWEEN COPPER PARTS" at 155.92,61.02 h1.4
  text "MINIMUM CLEARANCE BETWEEN :" at 156.245,57.99 h1.4
  text "NON-PLATED HOLES & COPPER PARTS :" at 156.245,54.99 h1.4
  text "FOR FULL BOARD OUTLINE AND ITS CUTOUTS DEFINITION, / REFER TO BOARD OUTLINE GERBER FILE" at -1.09,54.97 h2
  text "0.5mm" at 202.41,54.92 h1.4
  text "BOARD EDGE & COPPER PARTS :" at 156.245,51.99 h1.4
  text "0.50mm" at 194.245,51.99 h1.4
  text "SOLDER MASK EXPANSION FROM PAD EDGE :" at 156.245,48.99 h1.4
  text "0.05mm" at 209.245,48.99 h1.4
  text "VIAS FREE OF SOLDER MASK WITH 0.05mm EXPANSION" at 155.96,44.62 h1.4
  text "FROM VIA HOLE EDGE" at 155.86,42.02 h1.4
  text "MINIMUM SOLDER MASK SLIVER" at 156.58,36.775 h1.4
  text "0.10mm" at 215.635,36.775 h1.4
  text "SPECIFIC AND LOCAL VALUES" at 174.11,29.47 h1.75
  text "NONE" at 190.36,24.57 h1.4
  text "NOTES WHICH REFER TO IPC6012 SPECIFICATION /  IMPLY USE OF DOCUMENT LAST REVISION" at 158.66,3.72 h1.5
  text "1-" at 153.19,-3.28 h1.5
  text "MANUFACTURING ACCORDING TO" at 157.19,-3.28 h1.5
  text "IPC-6012 CLASS 2" at 197.19,-3.28 h1.5
  text "2-" at 153.19,-7.28 h1.5
  text "MATERIAL :" at 157.19,-7.28 h1.5
  text "FR4 TG 135 MINI - LOW CTE -" at 172.74,-7.38 h1.5
  text "3-" at 153.19,-11.28 h1.5
  text "HOLES PLATING :" at 157.19,-11.28 h1.5
  text "COPPER PLATING ACCORDING TO" at 180.19,-11.28 h1.5
  text "IPC-6012 RELATED TABLES" at 180.19,-14.28 h1.5
  text "4-" at 153.163,-17.528 h1.5
  text "COPPER WEIGHT : SEE LAYERS STACK-UP." at 158.878,-17.528 h1.5
  text "ACCORDING TO IPC-6012 RELATED TABLES:" at 158.878,-19.978 h1.5
  text "(INTERNAL , EXTERNAL STARTING FOIL)" at 158.878,-22.428 h1.5
  text "5-" at 153.163,-26.658 h1.5
  text "EXTERNAL LAYERS CHEMICAL PLATING:" at 158.878,-26.658 h1.5
  text "GOLD OVER NICKEL ACCORDING TO" at 159.19,-29.28 h1.5
  text "IPC6012 RELATED TABLE -  CODE ENIG" at 159.19,-32.28 h1.5
  text "Symbol" at -39.845,-35.506 h1.83
  text "Count" at -26.996,-35.506 h1.83
  text "Hole Size" at -11.76,-35.506 h1.83
  text "Plated" at 6.574,-35.506 h1.83
  text "Via/Pad" at 19.423,-35.506 h1.83
  text "6-" at 153.273,-37.628 h1.5
  text "SOLDER RESIST :" at 158.988,-37.628 h1.5
  text "225" at -26.996,-39.316 h1.52
  text "0.30mm" at -11.76,-39.316 h1.52
  text "PTH" at 6.574,-39.316 h1.52
  text "Via" at 19.423,-39.316 h1.52
  text "S" at -40.584,-39.57 h1.69
  text "LIQUID PHOTOIMAGEABLE" at 159.19,-40.28 h1.5
  text "TOP AND BOTTOM LAYERS" at 193.19,-40.28 h1.5
  text "LAYERS STACK-UP" at 83.08,-43.03 h2.1
  text "10" at -26.996,-43.126 h1.52
  text "0.50mm" at -11.76,-43.126 h1.52
  text "PTH" at 6.574,-43.126 h1.52
  text "Via" at 19.423,-43.126 h1.52
  text "COLOR :" at 159.19,-43.28 h1.5
  text "BLUE" at 170.19,-43.28 h1.5
  text "2" at -26.996,-46.936 h1.52
  text "0.90mm" at -11.76,-46.936 h1.52
  text "PTH" at 6.574,-46.936 h1.52
  text "Pad" at 19.423,-46.936 h1.52
  text "TOP LAYER" at 88.08,-48.03 h1.75
  text "F1:17µ" at 70.33,-49.405 h1.4
  text "7-" at 153.273,-49.758 h1.5
  text "SILK SCREEN PRINTING" at 158.988,-49.758 h1.5
  text "TOP AND BOTTOM LAYERS" at 193.19,-50.28 h1.5
  text "84" at -26.996,-50.746 h1.52
  text "1.00mm" at -11.76,-50.746 h1.52
  text "PTH" at 6.574,-50.746 h1.52
  text "Pad" at 19.423,-50.746 h1.52
  text "B" at -40.584,-51 h1.69
  text "EPOXYDE WHITE INK" at 159.19,-52.28 h1.5
  text "2" at -26.996,-54.556 h1.52
  text "3.20mm" at -11.76,-54.556 h1.52
  text "NPTH" at 6.574,-54.556 h1.52
  text "Pad" at 19.423,-54.556 h1.52
  text "X" at -40.584,-54.81 h1.69
  text "F2:17µ" at 69.695,-55.12 h1.4
  text "8-" at 153.908,-57.728 h1.5
  text "PACKING PAPER WITH CORROSION INHIBITOR" at 158.988,-57.728 h1.5
  text "323 Total" at -26.996,-58.366 h1.52
  text "F3:17µ" at 69.695,-60.2 h1.4
  text "9-" at 153.958,-64.078 h1.5
  text "RoHS COMPLIANT PRODUCT" at 159.038,-64.078 h1.5
  text "1.2 +/-10%" at 127.66,-64.48 h1.4 r90
  text "F4:17µ" at 69.695,-65.915 h1.4
  text "BOTTOM LAYER" at 85.08,-71.03 h1.75
  text "Hole Size shall be taken as follow : / - PTH PAD : Finished Size / - PTH VIA : Drill Size / - Any NPTH : Drill Size" at -34.827,-78.65 h1.5
  text "Hole Size Tolerance (unless otherwise specified):" at -34.724,-84.658 h1.5
  text "PTH <1.6mm: +0.1/-0.05" at -28.515,-87.03 h1.5
  text "PTH >1.6mm: +0.15/-0.1" at -28.565,-89.97 h1.5
  text "NPTH: +/-0.1" at -28.565,-93.42 h1.5
  text "Vias: No requirement regarding to the finished hole size" at -28.785,-99.35 h1.5
  text "DRILL DRAWING" at 152.91,-108.78 h2
  text "WARNING: / Drill letters are only intended to provide / an overview of the drill map. They may not / match with the exact holes location. / They shall not be used for drill process." at -28.065,-117.43 h1.5
  text "01/01" at 241.91,-134.28 h2.1
Cartouche Top:
  drawing of 432 lines, arcs and shapes, not listed
  text "TITLE :" at 80.047,-101.381 h2.1
  text ".Board_Reference" at 103,-101.381 h2.1
  text "GENERAL TOL." at 232.41,-102.28 h1.4
  text "+/- 0,2" at 234.41,-108.28 h1.75
  text "DOCUMENT :" at 80.047,-109.001 h2.1
  text "CHECKED" at 180.41,-114.28 h1.05
  text "APPROVED" at 208.41,-114.28 h1.05
  text "SCALE :" at 104.41,-115.28 h1.05
  text "DRAWN :" at 131,-115.28 h1.4
  text "STMICROELECTRONICS" at 142,-115.28 h1.4
  text "1/1" at 116.231,-115.996 h2.1
  text "DATE :" at 131,-119.28 h1.4
  text ".Board_Document_Date" at 142,-119.28 h1.4
  text "UNIT. :" at 105.41,-120.28 h1.05
  text "mm" at 117.41,-120.28 h1.4
  text "DOCUMENT REFERENCE" at 183.41,-124.28 h1.4
  text "PART NUMBER" at 176.41,-128.28 h1.4
  text "FORMAT" at 225.41,-128.28 h1.4
  text "SHEET" at 243.41,-128.28 h1.4
  text "STMICROELECTRONICS" at 101.6,-133 h1.75
  text "3" at 229.41,-134.28 h2.1
  text ".Board_Revision" at 244.7,-140.28 h1.4
  text "VER" at 249.713,-140.28 h1.4
Cartouche bottom:
  drawing of 432 lines, arcs and shapes, not listed
  text ".Board_Reference" at 10,-101.381 h2.1
  text "TITLE :" at 39.407,-101.381 h2.1
  text "GENERAL TOL." at -112.956,-102.28 h1.4
  text "+/- 0,2" at -114.956,-108.28 h1.75
  text "DOCUMENT :" at 39.407,-109.001 h2.1
  text "APPROVED" at -88.956,-114.28 h1.05
  text "CHECKED" at -60.956,-114.28 h1.05
  text "BE TECH" at -34.956,-115.28 h1.4
  text "DRAWN :" at -11.956,-115.28 h1.4
  text "SCALE :" at 15.044,-115.28 h1.05
  text "1/1" at 3.223,-115.996 h2.1
  text ".Board_Document_Date" at -34.956,-119.28 h1.4
  text "DATE :" at -12.956,-119.28 h1.4
  text "mm" at 2.044,-120.28 h1.4
  text "UNIT. :" at 14.044,-120.28 h1.05
  text "DOCUMENT REFERENCE" at -63.956,-124.28 h1.4
  text "ST MICROELECTRONICS" at 19.68,-125.79 h1.75
  text "SHEET" at -123.956,-128.28 h1.4
  text "FORMAT" at -105.956,-128.28 h1.4
  text "PART NUMBER" at -56.956,-128.28 h1.4
  text "SKY SOPHIA BATIMENT B" at 17.91,-128.87 h1.4
  text "776 RUE ALBERT CAQUOT" at 17.91,-131.87 h1.4
  text "3" at -109.956,-134.28 h2.1
  text "SOPHIA ANTIPOLIS" at 18.017,-134.769 h1.4
  text "06410 BIOT" at 17.79,-137.68 h1.4
  text ".Board_Revision" at -124.69,-140.23 h1.5
  text "REV" at -129.956,-140.28 h1.4
  text "FRANCE" at 17.517,-140.769 h1.4
Board:
  lines w0.2: 59.6,35.484 59.701,35.484 59.888,35.407 60.031,35.264 60.108,35.077 60.108,26.663 60.108,26.562 60.031,26.375 59.888,26.232 59.701,26.155 59.499,26.155 59.312,26.232 59.169,26.375 59.092,26.562 59.092,34.976 59.092,35.077 59.169,35.264 59.312,35.407 59.499,35.484 59.6,35.484 ; 59.6,35.484 59.6,35.484 ; 60.108,37.254 60.108,37.254 ; 60.108,37.254 60.108,37.153 60.031,36.966 59.888,36.823 59.701,36.746 59.6,36.746 59.499,36.746 59.312,36.823 59.169,36.966 59.092,37.153 59.092,37.254 59.092,50.77 -0.687,50.77 -1.077,50.719 -1.458,50.617 -1.821,50.466 -2.162,50.269 -2.475,50.029 -2.753,49.751 -2.993,49.439 -3.19,49.098 -3.341,48.734 -3.443,48.353 -3.494,47.963 -3.494,47.766 -3.49,42.77 17.51,42.77 cw(c17.51,41.77) 18.51,41.77 18.51,6.77 cw(c17.51,6.77) 17.51,5.77 -3.49,5.77 -3.49,-0.427 -3.439,-0.817 -3.337,-1.196 -3.186,-1.56 -2.99,-1.9 -2.75,-2.212 -2.472,-2.49 -2.16,-2.73 -1.82,-2.926 -1.456,-3.077 -1.077,-3.179 -0.687,-3.23 59.092,-3.23 59.092,10.439 59.169,10.626 59.312,10.769 59.499,10.846 59.701,10.846 59.888,10.769 60.031,10.626 60.108,10.439 60.108,-3.23 97.664,-3.23 98.054,-3.179 98.434,-3.077 98.797,-2.926 99.138,-2.73 99.45,-2.49 99.728,-2.212 99.967,-1.9 100.164,-1.56 100.314,-1.196 100.416,-0.817 100.467,-0.427 100.467,47.967 100.416,48.357 100.314,48.736 100.164,49.1 99.967,49.44 99.728,49.752 99.45,50.03 99.138,50.27 98.797,50.466 98.434,50.617 98.054,50.719 97.664,50.77 60.108,50.77 60.108,37.254 ; 59.092,12.515 59.169,12.328 59.312,12.185 59.499,12.108 59.701,12.108 59.888,12.185 60.031,12.328 60.108,12.515 60.108,20.903 60.031,21.09 59.888,21.233 59.701,21.31 59.499,21.31 59.312,21.233 59.169,21.09 59.092,20.903 59.092,12.515

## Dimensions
-0.662,-0.427 to -10.535,-10.23 on Drill Drawing
-3.49,-0.427 to 100.467,-0.427 on Drill Drawing
-0.687,-3.23 to -0.687,50.77 on Drill Drawing
97.664,-3.23 to 98.51,23.77 on Drill Drawing
100.467,-0.427 to 98.51,23.77 on Drill Drawing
